# Generated by OpenFakeRAM
VERSION 5.7 ;
BUSBITCHARS "[]" ;
PROPERTYDEFINITIONS
  MACRO width INTEGER ;
  MACRO depth INTEGER ;
  MACRO banks INTEGER ;
END PROPERTYDEFINITIONS
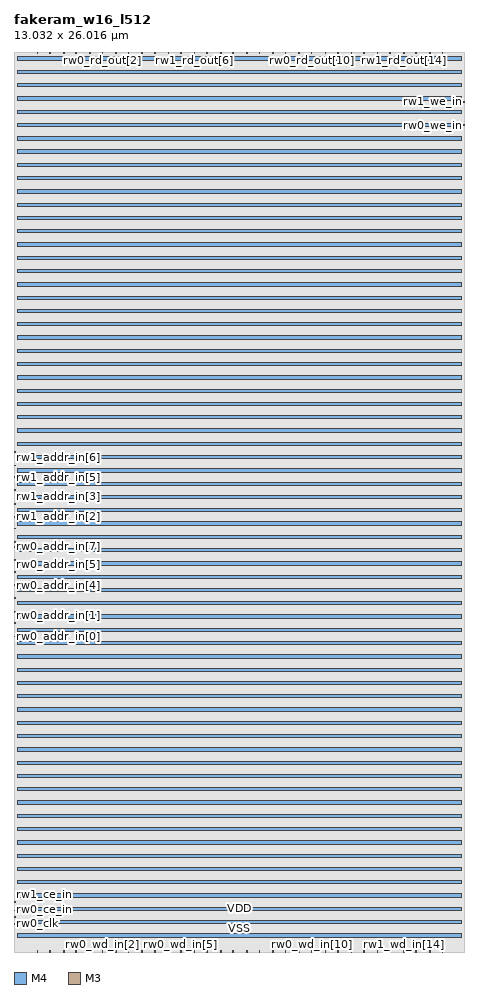
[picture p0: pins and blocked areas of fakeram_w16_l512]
MACRO fakeram_w16_l512
  PROPERTY width 16 ;
  PROPERTY depth 256 ;
  PROPERTY banks 1 ;
  FOREIGN fakeram_w16_l512 0 0 ;
  SYMMETRY X Y R90 ;
  SIZE 13.032 BY 26.016 ;
  CLASS BLOCK ;
  PIN rw0_clk
    DIRECTION INPUT ;
    USE SIGNAL ;
    SHAPE ABUTMENT ;
    PORT
      LAYER M4 ;
      RECT 0.000 0.804 0.048 0.828 ;
    END
  END rw0_clk
  PIN rw0_ce_in
    DIRECTION INPUT ;
    USE SIGNAL ;
    SHAPE ABUTMENT ;
    PORT
      LAYER M4 ;
      RECT 0.000 0.996 0.048 1.020 ;
    END
  END rw0_ce_in
  PIN rw1_clk
    DIRECTION INPUT ;
    USE SIGNAL ;
    SHAPE ABUTMENT ;
    PORT
      LAYER M4 ;
      RECT 0.000 1.188 0.048 1.212 ;
    END
  END rw1_clk
  PIN rw1_ce_in
    DIRECTION INPUT ;
    USE SIGNAL ;
    SHAPE ABUTMENT ;
    PORT
      LAYER M4 ;
      RECT 0.000 1.428 0.048 1.452 ;
    END
  END rw1_ce_in
  PIN rw0_addr_in[0]
    DIRECTION INPUT ;
    USE SIGNAL ;
    SHAPE ABUTMENT ;
    PORT
      LAYER M4 ;
      RECT 0.000 9.108 0.048 9.132 ;
    END
  END rw0_addr_in[0]
  PIN rw0_addr_in[1]
    DIRECTION INPUT ;
    USE SIGNAL ;
    SHAPE ABUTMENT ;
    PORT
      LAYER M4 ;
      RECT 0.000 9.492 0.048 9.516 ;
    END
  END rw0_addr_in[1]
  PIN rw0_addr_in[2]
    DIRECTION INPUT ;
    USE SIGNAL ;
    SHAPE ABUTMENT ;
    PORT
      LAYER M4 ;
      RECT 0.000 9.828 0.048 9.852 ;
    END
  END rw0_addr_in[2]
  PIN rw0_addr_in[3]
    DIRECTION INPUT ;
    USE SIGNAL ;
    SHAPE ABUTMENT ;
    PORT
      LAYER M4 ;
      RECT 0.000 10.212 0.048 10.236 ;
    END
  END rw0_addr_in[3]
  PIN rw0_addr_in[4]
    DIRECTION INPUT ;
    USE SIGNAL ;
    SHAPE ABUTMENT ;
    PORT
      LAYER M4 ;
      RECT 0.000 10.596 0.048 10.620 ;
    END
  END rw0_addr_in[4]
  PIN rw0_addr_in[5]
    DIRECTION INPUT ;
    USE SIGNAL ;
    SHAPE ABUTMENT ;
    PORT
      LAYER M4 ;
      RECT 0.000 10.980 0.048 11.004 ;
    END
  END rw0_addr_in[5]
  PIN rw0_addr_in[6]
    DIRECTION INPUT ;
    USE SIGNAL ;
    SHAPE ABUTMENT ;
    PORT
      LAYER M4 ;
      RECT 0.000 11.316 0.048 11.340 ;
    END
  END rw0_addr_in[6]
  PIN rw0_addr_in[7]
    DIRECTION INPUT ;
    USE SIGNAL ;
    SHAPE ABUTMENT ;
    PORT
      LAYER M4 ;
      RECT 0.000 11.700 0.048 11.724 ;
    END
  END rw0_addr_in[7]
  PIN rw1_addr_in[0]
    DIRECTION INPUT ;
    USE SIGNAL ;
    SHAPE ABUTMENT ;
    PORT
      LAYER M4 ;
      RECT 0.000 11.844 0.048 11.868 ;
    END
  END rw1_addr_in[0]
  PIN rw1_addr_in[1]
    DIRECTION INPUT ;
    USE SIGNAL ;
    SHAPE ABUTMENT ;
    PORT
      LAYER M4 ;
      RECT 0.000 12.228 0.048 12.252 ;
    END
  END rw1_addr_in[1]
  PIN rw1_addr_in[2]
    DIRECTION INPUT ;
    USE SIGNAL ;
    SHAPE ABUTMENT ;
    PORT
      LAYER M4 ;
      RECT 0.000 12.564 0.048 12.588 ;
    END
  END rw1_addr_in[2]
  PIN rw1_addr_in[3]
    DIRECTION INPUT ;
    USE SIGNAL ;
    SHAPE ABUTMENT ;
    PORT
      LAYER M4 ;
      RECT 0.000 12.948 0.048 12.972 ;
    END
  END rw1_addr_in[3]
  PIN rw1_addr_in[4]
    DIRECTION INPUT ;
    USE SIGNAL ;
    SHAPE ABUTMENT ;
    PORT
      LAYER M4 ;
      RECT 0.000 13.332 0.048 13.356 ;
    END
  END rw1_addr_in[4]
  PIN rw1_addr_in[5]
    DIRECTION INPUT ;
    USE SIGNAL ;
    SHAPE ABUTMENT ;
    PORT
      LAYER M4 ;
      RECT 0.000 13.716 0.048 13.740 ;
    END
  END rw1_addr_in[5]
  PIN rw1_addr_in[6]
    DIRECTION INPUT ;
    USE SIGNAL ;
    SHAPE ABUTMENT ;
    PORT
      LAYER M4 ;
      RECT 0.000 14.052 0.048 14.076 ;
    END
  END rw1_addr_in[6]
  PIN rw1_addr_in[7]
    DIRECTION INPUT ;
    USE SIGNAL ;
    SHAPE ABUTMENT ;
    PORT
      LAYER M4 ;
      RECT 0.000 14.436 0.048 14.460 ;
    END
  END rw1_addr_in[7]
  PIN rw1_rd_out[0]
    DIRECTION OUTPUT ;
    USE SIGNAL ;
    SHAPE ABUTMENT ;
    PORT
      LAYER M3 ;
      RECT 0.675 25.980 0.693 26.016 ;
    END
  END rw1_rd_out[0]
  PIN rw0_rd_out[0]
    DIRECTION OUTPUT ;
    USE SIGNAL ;
    SHAPE ABUTMENT ;
    PORT
      LAYER M3 ;
      RECT 1.035 25.980 1.053 26.016 ;
    END
  END rw0_rd_out[0]
  PIN rw1_rd_out[1]
    DIRECTION OUTPUT ;
    USE SIGNAL ;
    SHAPE ABUTMENT ;
    PORT
      LAYER M3 ;
      RECT 1.431 25.980 1.449 26.016 ;
    END
  END rw1_rd_out[1]
  PIN rw0_rd_out[1]
    DIRECTION OUTPUT ;
    USE SIGNAL ;
    SHAPE ABUTMENT ;
    PORT
      LAYER M3 ;
      RECT 1.791 25.980 1.809 26.016 ;
    END
  END rw0_rd_out[1]
  PIN rw1_rd_out[2]
    DIRECTION OUTPUT ;
    USE SIGNAL ;
    SHAPE ABUTMENT ;
    PORT
      LAYER M3 ;
      RECT 2.187 25.980 2.205 26.016 ;
    END
  END rw1_rd_out[2]
  PIN rw0_rd_out[2]
    DIRECTION OUTPUT ;
    USE SIGNAL ;
    SHAPE ABUTMENT ;
    PORT
      LAYER M3 ;
      RECT 2.547 25.980 2.565 26.016 ;
    END
  END rw0_rd_out[2]
  PIN rw1_rd_out[3]
    DIRECTION OUTPUT ;
    USE SIGNAL ;
    SHAPE ABUTMENT ;
    PORT
      LAYER M3 ;
      RECT 2.943 25.980 2.961 26.016 ;
    END
  END rw1_rd_out[3]
  PIN rw0_rd_out[3]
    DIRECTION OUTPUT ;
    USE SIGNAL ;
    SHAPE ABUTMENT ;
    PORT
      LAYER M3 ;
      RECT 3.303 25.980 3.321 26.016 ;
    END
  END rw0_rd_out[3]
  PIN rw1_rd_out[4]
    DIRECTION OUTPUT ;
    USE SIGNAL ;
    SHAPE ABUTMENT ;
    PORT
      LAYER M3 ;
      RECT 3.699 25.980 3.717 26.016 ;
    END
  END rw1_rd_out[4]
  PIN rw0_rd_out[4]
    DIRECTION OUTPUT ;
    USE SIGNAL ;
    SHAPE ABUTMENT ;
    PORT
      LAYER M3 ;
      RECT 4.059 25.980 4.077 26.016 ;
    END
  END rw0_rd_out[4]
  PIN rw1_rd_out[5]
    DIRECTION OUTPUT ;
    USE SIGNAL ;
    SHAPE ABUTMENT ;
    PORT
      LAYER M3 ;
      RECT 4.455 25.980 4.473 26.016 ;
    END
  END rw1_rd_out[5]
  PIN rw0_rd_out[5]
    DIRECTION OUTPUT ;
    USE SIGNAL ;
    SHAPE ABUTMENT ;
    PORT
      LAYER M3 ;
      RECT 4.815 25.980 4.833 26.016 ;
    END
  END rw0_rd_out[5]
  PIN rw1_rd_out[6]
    DIRECTION OUTPUT ;
    USE SIGNAL ;
    SHAPE ABUTMENT ;
    PORT
      LAYER M3 ;
      RECT 5.211 25.980 5.229 26.016 ;
    END
  END rw1_rd_out[6]
  PIN rw0_rd_out[6]
    DIRECTION OUTPUT ;
    USE SIGNAL ;
    SHAPE ABUTMENT ;
    PORT
      LAYER M3 ;
      RECT 5.571 25.980 5.589 26.016 ;
    END
  END rw0_rd_out[6]
  PIN rw1_rd_out[7]
    DIRECTION OUTPUT ;
    USE SIGNAL ;
    SHAPE ABUTMENT ;
    PORT
      LAYER M3 ;
      RECT 5.967 25.980 5.985 26.016 ;
    END
  END rw1_rd_out[7]
  PIN rw0_rd_out[7]
    DIRECTION OUTPUT ;
    USE SIGNAL ;
    SHAPE ABUTMENT ;
    PORT
      LAYER M3 ;
      RECT 6.327 25.980 6.345 26.016 ;
    END
  END rw0_rd_out[7]
  PIN rw1_rd_out[8]
    DIRECTION OUTPUT ;
    USE SIGNAL ;
    SHAPE ABUTMENT ;
    PORT
      LAYER M3 ;
      RECT 6.723 25.980 6.741 26.016 ;
    END
  END rw1_rd_out[8]
  PIN rw0_rd_out[8]
    DIRECTION OUTPUT ;
    USE SIGNAL ;
    SHAPE ABUTMENT ;
    PORT
      LAYER M3 ;
      RECT 7.083 25.980 7.101 26.016 ;
    END
  END rw0_rd_out[8]
  PIN rw1_rd_out[9]
    DIRECTION OUTPUT ;
    USE SIGNAL ;
    SHAPE ABUTMENT ;
    PORT
      LAYER M3 ;
      RECT 7.479 25.980 7.497 26.016 ;
    END
  END rw1_rd_out[9]
  PIN rw0_rd_out[9]
    DIRECTION OUTPUT ;
    USE SIGNAL ;
    SHAPE ABUTMENT ;
    PORT
      LAYER M3 ;
      RECT 7.839 25.980 7.857 26.016 ;
    END
  END rw0_rd_out[9]
  PIN rw1_rd_out[10]
    DIRECTION OUTPUT ;
    USE SIGNAL ;
    SHAPE ABUTMENT ;
    PORT
      LAYER M3 ;
      RECT 8.235 25.980 8.253 26.016 ;
    END
  END rw1_rd_out[10]
  PIN rw0_rd_out[10]
    DIRECTION OUTPUT ;
    USE SIGNAL ;
    SHAPE ABUTMENT ;
    PORT
      LAYER M3 ;
      RECT 8.595 25.980 8.613 26.016 ;
    END
  END rw0_rd_out[10]
  PIN rw1_rd_out[11]
    DIRECTION OUTPUT ;
    USE SIGNAL ;
    SHAPE ABUTMENT ;
    PORT
      LAYER M3 ;
      RECT 8.991 25.980 9.009 26.016 ;
    END
  END rw1_rd_out[11]
  PIN rw0_rd_out[11]
    DIRECTION OUTPUT ;
    USE SIGNAL ;
    SHAPE ABUTMENT ;
    PORT
      LAYER M3 ;
      RECT 9.351 25.980 9.369 26.016 ;
    END
  END rw0_rd_out[11]
  PIN rw1_rd_out[12]
    DIRECTION OUTPUT ;
    USE SIGNAL ;
    SHAPE ABUTMENT ;
    PORT
      LAYER M3 ;
      RECT 9.747 25.980 9.765 26.016 ;
    END
  END rw1_rd_out[12]
  PIN rw0_rd_out[12]
    DIRECTION OUTPUT ;
    USE SIGNAL ;
    SHAPE ABUTMENT ;
    PORT
      LAYER M3 ;
      RECT 10.107 25.980 10.125 26.016 ;
    END
  END rw0_rd_out[12]
  PIN rw1_rd_out[13]
    DIRECTION OUTPUT ;
    USE SIGNAL ;
    SHAPE ABUTMENT ;
    PORT
      LAYER M3 ;
      RECT 10.503 25.980 10.521 26.016 ;
    END
  END rw1_rd_out[13]
  PIN rw0_rd_out[13]
    DIRECTION OUTPUT ;
    USE SIGNAL ;
    SHAPE ABUTMENT ;
    PORT
      LAYER M3 ;
      RECT 10.863 25.980 10.881 26.016 ;
    END
  END rw0_rd_out[13]
  PIN rw1_rd_out[14]
    DIRECTION OUTPUT ;
    USE SIGNAL ;
    SHAPE ABUTMENT ;
    PORT
      LAYER M3 ;
      RECT 11.259 25.980 11.277 26.016 ;
    END
  END rw1_rd_out[14]
  PIN rw0_rd_out[14]
    DIRECTION OUTPUT ;
    USE SIGNAL ;
    SHAPE ABUTMENT ;
    PORT
      LAYER M3 ;
      RECT 11.619 25.980 11.637 26.016 ;
    END
  END rw0_rd_out[14]
  PIN rw1_rd_out[15]
    DIRECTION OUTPUT ;
    USE SIGNAL ;
    SHAPE ABUTMENT ;
    PORT
      LAYER M3 ;
      RECT 12.015 25.980 12.033 26.016 ;
    END
  END rw1_rd_out[15]
  PIN rw0_rd_out[15]
    DIRECTION OUTPUT ;
    USE SIGNAL ;
    SHAPE ABUTMENT ;
    PORT
      LAYER M3 ;
      RECT 12.375 25.980 12.393 26.016 ;
    END
  END rw0_rd_out[15]
  PIN rw0_we_in
    DIRECTION INPUT ;
    USE SIGNAL ;
    SHAPE ABUTMENT ;
    PORT
      LAYER M4 ;
      RECT 12.984 23.892 13.032 23.916 ;
    END
  END rw0_we_in
  PIN rw1_we_in
    DIRECTION INPUT ;
    USE SIGNAL ;
    SHAPE ABUTMENT ;
    PORT
      LAYER M4 ;
      RECT 12.984 24.564 13.032 24.588 ;
    END
  END rw1_we_in
  PIN rw1_wd_in[0]
    DIRECTION INPUT ;
    USE SIGNAL ;
    SHAPE ABUTMENT ;
    PORT
      LAYER M3 ;
      RECT 0.675 0.000 0.693 0.036 ;
    END
  END rw1_wd_in[0]
  PIN rw0_wd_in[0]
    DIRECTION INPUT ;
    USE SIGNAL ;
    SHAPE ABUTMENT ;
    PORT
      LAYER M3 ;
      RECT 1.035 0.000 1.053 0.036 ;
    END
  END rw0_wd_in[0]
  PIN rw1_wd_in[1]
    DIRECTION INPUT ;
    USE SIGNAL ;
    SHAPE ABUTMENT ;
    PORT
      LAYER M3 ;
      RECT 1.431 0.000 1.449 0.036 ;
    END
  END rw1_wd_in[1]
  PIN rw0_wd_in[1]
    DIRECTION INPUT ;
    USE SIGNAL ;
    SHAPE ABUTMENT ;
    PORT
      LAYER M3 ;
      RECT 1.791 0.000 1.809 0.036 ;
    END
  END rw0_wd_in[1]
  PIN rw1_wd_in[2]
    DIRECTION INPUT ;
    USE SIGNAL ;
    SHAPE ABUTMENT ;
    PORT
      LAYER M3 ;
      RECT 2.187 0.000 2.205 0.036 ;
    END
  END rw1_wd_in[2]
  PIN rw0_wd_in[2]
    DIRECTION INPUT ;
    USE SIGNAL ;
    SHAPE ABUTMENT ;
    PORT
      LAYER M3 ;
      RECT 2.547 0.000 2.565 0.036 ;
    END
  END rw0_wd_in[2]
  PIN rw1_wd_in[3]
    DIRECTION INPUT ;
    USE SIGNAL ;
    SHAPE ABUTMENT ;
    PORT
      LAYER M3 ;
      RECT 2.943 0.000 2.961 0.036 ;
    END
  END rw1_wd_in[3]
  PIN rw0_wd_in[3]
    DIRECTION INPUT ;
    USE SIGNAL ;
    SHAPE ABUTMENT ;
    PORT
      LAYER M3 ;
      RECT 3.303 0.000 3.321 0.036 ;
    END
  END rw0_wd_in[3]
  PIN rw1_wd_in[4]
    DIRECTION INPUT ;
    USE SIGNAL ;
    SHAPE ABUTMENT ;
    PORT
      LAYER M3 ;
      RECT 3.699 0.000 3.717 0.036 ;
    END
  END rw1_wd_in[4]
  PIN rw0_wd_in[4]
    DIRECTION INPUT ;
    USE SIGNAL ;
    SHAPE ABUTMENT ;
    PORT
      LAYER M3 ;
      RECT 4.059 0.000 4.077 0.036 ;
    END
  END rw0_wd_in[4]
  PIN rw1_wd_in[5]
    DIRECTION INPUT ;
    USE SIGNAL ;
    SHAPE ABUTMENT ;
    PORT
      LAYER M3 ;
      RECT 4.455 0.000 4.473 0.036 ;
    END
  END rw1_wd_in[5]
  PIN rw0_wd_in[5]
    DIRECTION INPUT ;
    USE SIGNAL ;
    SHAPE ABUTMENT ;
    PORT
      LAYER M3 ;
      RECT 4.815 0.000 4.833 0.036 ;
    END
  END rw0_wd_in[5]
  PIN rw1_wd_in[6]
    DIRECTION INPUT ;
    USE SIGNAL ;
    SHAPE ABUTMENT ;
    PORT
      LAYER M3 ;
      RECT 5.211 0.000 5.229 0.036 ;
    END
  END rw1_wd_in[6]
  PIN rw0_wd_in[6]
    DIRECTION INPUT ;
    USE SIGNAL ;
    SHAPE ABUTMENT ;
    PORT
      LAYER M3 ;
      RECT 5.571 0.000 5.589 0.036 ;
    END
  END rw0_wd_in[6]
  PIN rw1_wd_in[7]
    DIRECTION INPUT ;
    USE SIGNAL ;
    SHAPE ABUTMENT ;
    PORT
      LAYER M3 ;
      RECT 5.967 0.000 5.985 0.036 ;
    END
  END rw1_wd_in[7]
  PIN rw0_wd_in[7]
    DIRECTION INPUT ;
    USE SIGNAL ;
    SHAPE ABUTMENT ;
    PORT
      LAYER M3 ;
      RECT 6.327 0.000 6.345 0.036 ;
    END
  END rw0_wd_in[7]
  PIN rw1_wd_in[8]
    DIRECTION INPUT ;
    USE SIGNAL ;
    SHAPE ABUTMENT ;
    PORT
      LAYER M3 ;
      RECT 6.723 0.000 6.741 0.036 ;
    END
  END rw1_wd_in[8]
  PIN rw0_wd_in[8]
    DIRECTION INPUT ;
    USE SIGNAL ;
    SHAPE ABUTMENT ;
    PORT
      LAYER M3 ;
      RECT 7.083 0.000 7.101 0.036 ;
    END
  END rw0_wd_in[8]
  PIN rw1_wd_in[9]
    DIRECTION INPUT ;
    USE SIGNAL ;
    SHAPE ABUTMENT ;
    PORT
      LAYER M3 ;
      RECT 7.479 0.000 7.497 0.036 ;
    END
  END rw1_wd_in[9]
  PIN rw0_wd_in[9]
    DIRECTION INPUT ;
    USE SIGNAL ;
    SHAPE ABUTMENT ;
    PORT
      LAYER M3 ;
      RECT 7.839 0.000 7.857 0.036 ;
    END
  END rw0_wd_in[9]
  PIN rw1_wd_in[10]
    DIRECTION INPUT ;
    USE SIGNAL ;
    SHAPE ABUTMENT ;
    PORT
      LAYER M3 ;
      RECT 8.235 0.000 8.253 0.036 ;
    END
  END rw1_wd_in[10]
  PIN rw0_wd_in[10]
    DIRECTION INPUT ;
    USE SIGNAL ;
    SHAPE ABUTMENT ;
    PORT
      LAYER M3 ;
      RECT 8.595 0.000 8.613 0.036 ;
    END
  END rw0_wd_in[10]
  PIN rw1_wd_in[11]
    DIRECTION INPUT ;
    USE SIGNAL ;
    SHAPE ABUTMENT ;
    PORT
      LAYER M3 ;
      RECT 8.991 0.000 9.009 0.036 ;
    END
  END rw1_wd_in[11]
  PIN rw0_wd_in[11]
    DIRECTION INPUT ;
    USE SIGNAL ;
    SHAPE ABUTMENT ;
    PORT
      LAYER M3 ;
      RECT 9.351 0.000 9.369 0.036 ;
    END
  END rw0_wd_in[11]
  PIN rw1_wd_in[12]
    DIRECTION INPUT ;
    USE SIGNAL ;
    SHAPE ABUTMENT ;
    PORT
      LAYER M3 ;
      RECT 9.747 0.000 9.765 0.036 ;
    END
  END rw1_wd_in[12]
  PIN rw0_wd_in[12]
    DIRECTION INPUT ;
    USE SIGNAL ;
    SHAPE ABUTMENT ;
    PORT
      LAYER M3 ;
      RECT 10.107 0.000 10.125 0.036 ;
    END
  END rw0_wd_in[12]
  PIN rw1_wd_in[13]
    DIRECTION INPUT ;
    USE SIGNAL ;
    SHAPE ABUTMENT ;
    PORT
      LAYER M3 ;
      RECT 10.503 0.000 10.521 0.036 ;
    END
  END rw1_wd_in[13]
  PIN rw0_wd_in[13]
    DIRECTION INPUT ;
    USE SIGNAL ;
    SHAPE ABUTMENT ;
    PORT
      LAYER M3 ;
      RECT 10.863 0.000 10.881 0.036 ;
    END
  END rw0_wd_in[13]
  PIN rw1_wd_in[14]
    DIRECTION INPUT ;
    USE SIGNAL ;
    SHAPE ABUTMENT ;
    PORT
      LAYER M3 ;
      RECT 11.259 0.000 11.277 0.036 ;
    END
  END rw1_wd_in[14]
  PIN rw0_wd_in[14]
    DIRECTION INPUT ;
    USE SIGNAL ;
    SHAPE ABUTMENT ;
    PORT
      LAYER M3 ;
      RECT 11.619 0.000 11.637 0.036 ;
    END
  END rw0_wd_in[14]
  PIN rw1_wd_in[15]
    DIRECTION INPUT ;
    USE SIGNAL ;
    SHAPE ABUTMENT ;
    PORT
      LAYER M3 ;
      RECT 12.015 0.000 12.033 0.036 ;
    END
  END rw1_wd_in[15]
  PIN rw0_wd_in[15]
    DIRECTION INPUT ;
    USE SIGNAL ;
    SHAPE ABUTMENT ;
    PORT
      LAYER M3 ;
      RECT 12.375 0.000 12.393 0.036 ;
    END
  END rw0_wd_in[15]
  PIN VSS
    DIRECTION INOUT ;
    USE GROUND ;
    PORT
      LAYER M4 ;
      RECT 0.096 0.816 12.936 0.912 ;
      RECT 0.096 1.584 12.936 1.680 ;
      RECT 0.096 2.352 12.936 2.448 ;
      RECT 0.096 3.120 12.936 3.216 ;
      RECT 0.096 3.888 12.936 3.984 ;
      RECT 0.096 4.656 12.936 4.752 ;
      RECT 0.096 5.424 12.936 5.520 ;
      RECT 0.096 6.192 12.936 6.288 ;
      RECT 0.096 6.960 12.936 7.056 ;
      RECT 0.096 7.728 12.936 7.824 ;
      RECT 0.096 8.496 12.936 8.592 ;
      RECT 0.096 9.264 12.936 9.360 ;
      RECT 0.096 10.032 12.936 10.128 ;
      RECT 0.096 10.800 12.936 10.896 ;
      RECT 0.096 11.568 12.936 11.664 ;
      RECT 0.096 12.336 12.936 12.432 ;
      RECT 0.096 13.104 12.936 13.200 ;
      RECT 0.096 13.872 12.936 13.968 ;
      RECT 0.096 14.640 12.936 14.736 ;
      RECT 0.096 15.408 12.936 15.504 ;
      RECT 0.096 16.176 12.936 16.272 ;
      RECT 0.096 16.944 12.936 17.040 ;
      RECT 0.096 17.712 12.936 17.808 ;
      RECT 0.096 18.480 12.936 18.576 ;
      RECT 0.096 19.248 12.936 19.344 ;
      RECT 0.096 20.016 12.936 20.112 ;
      RECT 0.096 20.784 12.936 20.880 ;
      RECT 0.096 21.552 12.936 21.648 ;
      RECT 0.096 22.320 12.936 22.416 ;
      RECT 0.096 23.088 12.936 23.184 ;
      RECT 0.096 23.856 12.936 23.952 ;
      RECT 0.096 24.624 12.936 24.720 ;
      RECT 0.096 25.392 12.936 25.488 ;
    END
  END VSS
  PIN VDD
    DIRECTION INOUT ;
    USE POWER ;
    PORT
      LAYER M4 ;
      RECT 0.096 0.432 12.936 0.528 ;
      RECT 0.096 1.200 12.936 1.296 ;
      RECT 0.096 1.968 12.936 2.064 ;
      RECT 0.096 2.736 12.936 2.832 ;
      RECT 0.096 3.504 12.936 3.600 ;
      RECT 0.096 4.272 12.936 4.368 ;
      RECT 0.096 5.040 12.936 5.136 ;
      RECT 0.096 5.808 12.936 5.904 ;
      RECT 0.096 6.576 12.936 6.672 ;
      RECT 0.096 7.344 12.936 7.440 ;
      RECT 0.096 8.112 12.936 8.208 ;
      RECT 0.096 8.880 12.936 8.976 ;
      RECT 0.096 9.648 12.936 9.744 ;
      RECT 0.096 10.416 12.936 10.512 ;
      RECT 0.096 11.184 12.936 11.280 ;
      RECT 0.096 11.952 12.936 12.048 ;
      RECT 0.096 12.720 12.936 12.816 ;
      RECT 0.096 13.488 12.936 13.584 ;
      RECT 0.096 14.256 12.936 14.352 ;
      RECT 0.096 15.024 12.936 15.120 ;
      RECT 0.096 15.792 12.936 15.888 ;
      RECT 0.096 16.560 12.936 16.656 ;
      RECT 0.096 17.328 12.936 17.424 ;
      RECT 0.096 18.096 12.936 18.192 ;
      RECT 0.096 18.864 12.936 18.960 ;
      RECT 0.096 19.632 12.936 19.728 ;
      RECT 0.096 20.400 12.936 20.496 ;
      RECT 0.096 21.168 12.936 21.264 ;
      RECT 0.096 21.936 12.936 22.032 ;
      RECT 0.096 22.704 12.936 22.800 ;
      RECT 0.096 23.472 12.936 23.568 ;
      RECT 0.096 24.240 12.936 24.336 ;
      RECT 0.096 25.008 12.936 25.104 ;
      RECT 0.096 25.776 12.936 25.872 ;
    END
  END VDD
  OBS
    LAYER M1 ;
    RECT 0 0 13.032 26.016 ;
    LAYER M2 ;
    RECT 0 0 13.032 26.016 ;
    LAYER M3 ;
    RECT 0 0 13.032 26.016 ;
    LAYER M4 ;
    RECT 0 0 13.032 26.016 ;
  END
END fakeram_w16_l512

END LIBRARY
